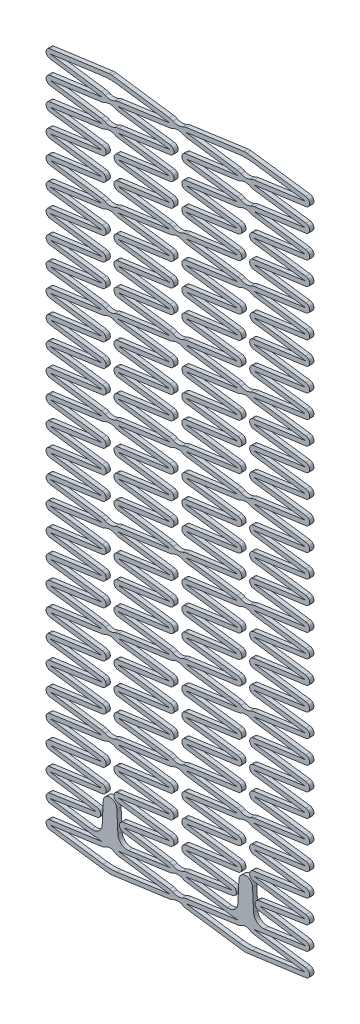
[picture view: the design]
SolidWorks part; units mm, degrees
ref_plane "Ebene vorne" through (0, 0, 0) normal (0, 0, 1) x (1, 0, 0)
ref_plane "Ebene oben" through (0, 0, 0) normal (0, 1, 0) x (1, 0, 0)
ref_plane "Ebene rechts" through (0, 0, 0) normal (1, 0, 0) x (0, 0, -1)
sketch "Skizze1" plane through (0, 0, 0) normal (0, 0, 1) x (1, 0, 0)
  line L0 (43.7003, 7.0015) -> (41.2898, 6.6632)
  line L1 (38.0663, 7.0015) -> (40.4767, 6.6632)
  line L2 (41.2898, 6.2523) -> (43.7003, 5.914)
  line L3 (40.4767, 6.2523) -> (38.0663, 5.914)
  line L4 (47.6978, 14.952) -> (50.1083, 14.6137)
  line L5 (46.8847, 14.952) -> (44.4743, 14.6137)
  line L6 (50.1083, 15.7012) -> (47.6978, 15.3629)
  line L7 (44.4743, 15.7012) -> (46.8847, 15.3629)
  line L8 (44.4743, 12.4388) -> (46.9247, 12.7771)
  line L9 (47.6578, 12.7771) -> (50.1083, 12.4388)
  line L10 (50.1083, 13.5263) -> (47.6578, 13.188)
  line L11 (44.4743, 13.5263) -> (46.9247, 13.188)
  line L12 (47.6978, 10.6022) -> (50.1083, 10.2639)
  line L13 (46.8847, 10.6022) -> (44.4743, 10.2639)
  line L14 (50.1083, 11.3513) -> (47.6978, 11.013)
  line L15 (44.4743, 11.3513) -> (46.8847, 11.013)
  line L16 (46.9247, 8.4272) -> (44.4743, 8.0889)
  line L17 (47.6578, 8.4272) -> (50.1083, 8.0889)
  line L18 (44.4743, 9.1764) -> (46.9247, 8.8381)
  line L19 (50.1083, 9.1764) -> (47.6578, 8.8381)
  line L20 (47.6978, 6.2523) -> (50.1083, 5.914)
  line L21 (46.8847, 6.2523) -> (44.4743, 5.914)
  line L22 (50.1083, 7.0015) -> (47.6978, 6.6632)
  line L23 (44.4743, 7.0015) -> (46.8847, 6.6632)
  line L24 (46.9247, 4.0773) -> (44.4743, 3.739)
  line L25 (47.6578, 4.0773) -> (50.1083, 3.739)
  line L26 (44.4743, 4.8265) -> (46.9247, 4.4882)
  line L27 (50.1083, 4.8265) -> (47.6578, 4.4882)
  line L28 (47.6978, 1.9024) -> (50.1083, 1.5641)
  line L29 (46.8847, 1.9024) -> (44.4743, 1.5641)
  line L30 (50.1083, 2.6516) -> (47.6978, 2.3133)
  line L31 (44.4743, 2.6516) -> (46.8847, 2.3133)
  line L32 (41.2703, 19.5074) -> (43.7207, 19.1691)
  line L33 (44.4538, 19.1691) -> (46.9043, 19.5074)
  line L34 (43.7207, 18.7582) -> (41.2703, 18.4199)
  line L35 (44.4538, 18.7582) -> (46.9043, 18.4199)
  line L36 (41.2703, 15.1575) -> (43.7207, 14.8192)
  line L37 (44.4538, 14.8192) -> (46.9043, 15.1575)
  line L38 (43.7207, 14.4083) -> (41.2703, 14.07)
  line L39 (44.4538, 14.4083) -> (46.9043, 14.07)
  line L40 (44.4538, 10.0584) -> (46.9043, 9.7201)
  line L41 (46.9043, 10.8076) -> (44.4538, 10.4693)
  line L42 (41.2703, 10.8076) -> (43.7207, 10.4693)
  line L43 (43.7207, 10.0584) -> (41.2703, 9.7201)
  line L44 (44.4538, 7.8835) -> (46.9043, 7.5452)
  line L45 (43.7207, 7.8835) -> (41.2703, 7.5452)
  line L46 (46.9043, 8.6327) -> (44.4538, 8.2944)
  line L47 (41.2703, 8.6327) -> (43.7207, 8.2944)
  line L48 (44.4538, 3.5336) -> (46.9043, 3.1953)
  line L49 (43.7207, 3.5336) -> (41.2703, 3.1953)
  line L50 (46.9043, 4.2828) -> (44.4538, 3.9445)
  line L51 (41.2703, 4.2828) -> (43.7207, 3.9445)
  line L52 (41.2498, 12.7771) -> (43.7003, 12.4388)
  line L53 (40.5167, 12.7771) -> (38.0663, 12.4388)
  line L54 (43.7003, 13.5263) -> (41.2498, 13.188)
  line L55 (38.0663, 13.5263) -> (40.5167, 13.188)
  line L56 (41.2498, 8.4272) -> (43.7003, 8.0889)
  line L57 (40.5167, 8.4272) -> (38.0663, 8.0889)
  line L58 (43.7003, 9.1764) -> (41.2498, 8.8381)
  line L59 (38.0663, 9.1764) -> (40.5167, 8.8381)
  line L60 (43.7003, 4.8265) -> (41.2498, 4.4882)
  line L61 (38.0663, 4.8265) -> (40.5167, 4.4882)
  line L62 (40.5167, 4.0773) -> (38.0663, 3.739)
  line L63 (41.2498, 4.0773) -> (43.7003, 3.739)
  line L64 (41.2703, 1.0204) -> (43.7207, 0.6821)
  line L65 (43.7207, 0.2712) -> (41.2703, -0.0671)
  line L66 (43.7003, 0.4766) -> (41.2498, 0.1383)
  line L67 (44.4538, 0.2712) -> (46.9043, -0.0671)
  line L68 (44.4743, 0.4766) -> (46.9247, 0.1383)
  line L69 (46.9043, 1.0204) -> (44.4538, 0.6821)
  line L70 (44.4743, -0.6108) -> (46.9247, -0.9491)
  line L71 (41.2703, -0.0671) -> (43.7207, -0.4054)
  line L72 (41.2498, -0.2725) -> (43.7003, -0.6108)
  line L73 (43.7207, -0.8163) -> (41.2703, -1.1546)
  line L74 (43.7003, -0.6108) -> (41.2498, -0.9491)
  line L75 (44.4538, -0.8163) -> (46.9043, -1.1546)
  line L76 (46.9247, -0.2725) -> (44.4743, -0.6108)
  line L77 (46.9043, -0.0671) -> (44.4538, -0.4054)
  line L78 (47.6783, 2.1078) -> (50.1287, 1.7695)
  line L79 (50.1287, 1.3587) -> (47.6783, 1.0204)
  line L80 (50.1083, 0.4766) -> (47.6578, 0.1383)
  line L81 (50.1287, 0.2712) -> (47.6783, -0.0671)
  line L82 (47.6783, 1.0204) -> (50.1287, 0.6821)
  line L83 (47.6578, -0.2725) -> (50.1083, -0.6108)
  line L84 (47.6783, -0.0671) -> (50.1287, -0.4054)
  line L85 (50.1083, -0.6108) -> (47.6578, -0.9491)
  line L86 (50.1287, -0.8163) -> (47.6783, -1.1546)
  line L87 (40.4963, 2.1078) -> (38.0458, 1.7695)
  line L88 (38.0458, 1.3587) -> (40.4963, 1.0204)
  line L89 (38.0663, 0.4766) -> (40.5167, 0.1383)
  line L90 (38.0458, 0.2712) -> (40.4963, -0.0671)
  line L91 (40.4963, 1.0204) -> (38.0458, 0.6821)
  line L92 (38.0663, -0.6108) -> (40.5167, -0.9491)
  line L93 (38.0458, -0.8163) -> (40.4963, -1.1546)
  line L94 (40.4963, -0.0671) -> (38.0458, -0.4054)
  line L95 (40.5167, -0.2725) -> (38.0663, -0.6108)
  line L96 (47.6783, 6.4577) -> (50.1287, 6.1194)
  line L97 (50.1287, 5.7086) -> (47.6783, 5.3702)
  line L98 (38.0458, 5.7086) -> (40.4963, 5.3702)
  line L99 (40.4963, 6.4577) -> (38.0458, 6.1194)
  line L100 (47.6783, 8.6327) -> (50.1287, 8.2944)
  line L101 (50.1287, 7.8835) -> (47.6783, 7.5452)
  line L102 (50.1287, 6.796) -> (47.6783, 6.4577)
  line L103 (47.6783, 7.5452) -> (50.1287, 7.2069)
  line L104 (44.4938, -6.2536) -> (46.9043, -6.5919)
  line L105 (41.2703, -6.5919) -> (43.6807, -6.2536)
  line L106 (41.529, -5.5045) -> (43.6807, -5.8428)
  line L107 (46.6456, -5.5045) -> (44.4938, -5.8428)
  line L108 (44.4938, -7.3411) -> (47.2006, -7.721)
  line L109 (40.974, -7.721) -> (43.6807, -7.3411)
  line L110 (41.2703, -6.5919) -> (43.6807, -6.9302)
  line L111 (46.9043, -6.5919) -> (44.4938, -6.9302)
  line L112 (40.2376, -5.5045) -> (38.0458, -5.8428)
  line L113 (40.258, -5.7099) -> (38.0663, -6.0482)
  line L114 (38.0458, -5.1661) -> (40.2376, -5.5045)
  line L115 (38.0663, -4.9607) -> (40.258, -5.299)
  line L116 (40.4963, 14.07) -> (38.0458, 13.7317)
  line L117 (40.4963, -4.417) -> (38.0458, -4.7553)
  line L118 (40.5167, -4.6224) -> (38.0663, -4.9607)
  line L119 (38.0458, 13.3208) -> (40.4963, 12.9825)
  line L120 (41.5085, -5.7099) -> (43.7003, -6.0482)
  line L121 (46.666, -5.7099) -> (44.4743, -6.0482)
  line L122 (50.1287, 13.3208) -> (47.6783, 12.9825)
  line L123 (47.6783, -4.417) -> (50.1287, -4.7553)
  line L124 (47.6578, -4.6224) -> (50.1083, -4.9607)
  line L125 (47.6783, 14.07) -> (50.1287, 13.7317)
  line L126 (47.9165, -5.299) -> (50.1083, -4.9607)
  line L127 (47.937, -5.5045) -> (50.1287, -5.1661)
  line L128 (47.937, -5.5045) -> (50.1287, -5.8428)
  line L129 (47.9165, -5.7099) -> (50.1083, -6.0482)
  line L130 (38.0663, -7.1357) -> (40.4767, -6.7974)
  line L131 (41.2898, -6.7974) -> (43.7003, -7.1357)
  line L132 (41.758, -6.3285) -> (43.7003, -6.0482)
  line L133 (47.6783, -6.5919) -> (50.1287, -6.2536)
  line L134 (50.1083, -7.1357) -> (47.6978, -6.7974)
  line L135 (50.1287, -6.9302) -> (47.6783, -6.5919)
  line L136 (47.3375, -7.7213) -> (50.1287, -7.3411)
  line L137 (47.6231, -7.4832) -> (50.1083, -7.1357)
  line L138 (44.4743, -7.1357) -> (46.8847, -6.7974)
  line L139 (46.9594, -7.4832) -> (44.4743, -7.1357)
  line L140 (41.2151, -7.4832) -> (43.7003, -7.1357)
  line L141 (40.0086, -6.3285) -> (38.0663, -6.0482)
  line L142 (40.4963, -6.5919) -> (38.0458, -6.2536)
  line L143 (38.0458, -6.9302) -> (40.4963, -6.5919)
  line L144 (40.5514, -7.4832) -> (38.0663, -7.1357)
  line L145 (40.837, -7.7213) -> (38.0458, -7.3411)
  line L146 (40.562, -4.9079) -> (40.5126, -5.9161)
  line L147 (41.2046, -4.9079) -> (41.254, -5.9161)
  line L148 (46.97, -4.9079) -> (46.9206, -5.9161)
  line L149 (47.6126, -4.9079) -> (47.662, -5.9161)
  line L150 (46.4166, -6.3285) -> (44.4743, -6.0482)
  line L151 (48.166, -6.3285) -> (50.1083, -6.0482)
  line L152 (38.0663, 24.401) -> (40.4767, 24.0627)
  line L153 (47.6578, 17.127) -> (50.1083, 16.7887)
  line L154 (47.6783, 17.3324) -> (50.1287, 16.9941)
  line L155 (47.6783, 17.3324) -> (50.1287, 17.6707)
  line L156 (47.6578, 17.5379) -> (50.1278, 17.8762)
  line L157 (47.6578, 21.4769) -> (50.1083, 21.1386)
  line L158 (47.6783, 21.6823) -> (50.1287, 21.344)
  line L159 (47.6783, 21.6823) -> (50.1287, 22.0206)
  line L160 (47.6578, 21.8877) -> (50.1083, 22.226)
  line L161 (44.4743, 20.0511) -> (46.9043, 19.7128)
  line L162 (44.4743, 22.226) -> (46.8847, 22.5643)
  line L163 (44.4538, 22.4315) -> (46.9043, 22.7698)
  line L164 (41.2498, 16.0395) -> (43.7003, 15.7012)
  line L165 (41.2498, 16.4504) -> (43.7003, 16.7887)
  line L166 (41.2498, 20.8003) -> (43.7003, 21.1386)
  line L167 (41.2498, 20.3894) -> (43.7003, 20.0511)
  line L168 (41.2898, 24.0627) -> (43.7003, 24.401)
  line L169 (41.2703, 23.8572) -> (43.6807, 24.1955)
  line L170 (41.2703, 23.8572) -> (43.7207, 23.5189)
  line L171 (41.2898, 23.6518) -> (43.7003, 23.3135)
  line L172 (47.6783, 23.8572) -> (50.1287, 23.5189)
  line L173 (47.6978, 23.6518) -> (50.1083, 23.3135)
  line L174 (50.1083, 23.3135) -> (47.6978, 22.9752)
  line L175 (50.1287, 23.1081) -> (47.6783, 22.7698)
  line L176 (47.6783, 22.7698) -> (50.1287, 22.4315)
  line L177 (47.6978, 22.5643) -> (50.1083, 22.226)
  line L178 (50.1083, 24.401) -> (47.6978, 24.0627)
  line L179 (50.1287, 24.1955) -> (47.6783, 23.8572)
  line L180 (47.3375, 24.9866) -> (50.1287, 24.6064)
  line L181 (47.6231, 24.7485) -> (50.1083, 24.401)
  line L182 (50.1287, 20.9331) -> (47.6783, 20.5948)
  line L183 (50.1083, 21.1386) -> (47.6578, 20.8003)
  line L184 (47.6783, 20.5948) -> (50.1287, 20.2565)
  line L185 (47.6578, 20.3894) -> (50.1278, 20.0511)
  line L186 (47.6783, 19.5074) -> (50.1287, 19.1691)
  line L187 (50.1083, 16.7887) -> (47.6578, 16.4504)
  line L188 (50.1287, 16.5833) -> (47.6783, 16.2449)
  line L189 (47.7174, 19.3019) -> (50.1278, 18.9636)
  line L190 (47.6783, 18.4199) -> (50.1287, 18.0816)
  line L191 (50.1287, 18.7582) -> (47.6783, 18.4199)
  line L192 (50.1278, 20.0511) -> (47.7174, 19.7128)
  line L193 (50.1287, 19.8457) -> (47.6783, 19.5074)
  line L194 (47.6783, 16.2449) -> (50.1287, 15.9066)
  line L195 (47.6578, 16.0395) -> (50.1083, 15.7012)
  line L196 (47.6783, 15.1575) -> (50.1287, 14.8192)
  line L197 (50.1287, 14.4083) -> (47.6783, 14.07)
  line L198 (50.1287, 15.4958) -> (47.6783, 15.1575)
  line L199 (44.4743, 24.401) -> (46.8847, 24.0627)
  line L200 (44.4938, 24.1955) -> (46.9043, 23.8572)
  line L201 (46.9043, 23.8572) -> (44.4538, 23.5189)
  line L202 (46.8847, 23.6518) -> (44.4743, 23.3135)
  line L203 (44.4743, 23.3135) -> (46.8847, 22.9752)
  line L204 (44.4538, 23.1081) -> (46.9043, 22.7698)
  line L205 (47.2006, 24.9863) -> (44.4938, 24.6064)
  line L206 (46.9594, 24.7485) -> (44.4743, 24.401)
  line L207 (44.4538, 22.0206) -> (46.9043, 21.6823)
  line L208 (44.4743, 22.226) -> (46.9247, 21.8877)
  line L209 (46.9247, 21.4769) -> (44.4743, 21.1386)
  line L210 (44.4743, 21.1386) -> (46.9247, 20.8003)
  line L211 (46.9043, 18.4199) -> (44.4538, 18.0816)
  line L212 (46.9043, 19.3019) -> (44.4938, 18.9636)
  line L213 (46.9247, 17.127) -> (44.4743, 16.7887)
  line L214 (44.4938, 17.8762) -> (46.9247, 17.5379)
  line L215 (44.4538, 17.6707) -> (46.9043, 17.3324)
  line L216 (46.9247, 20.3894) -> (44.4743, 20.0511)
  line L217 (44.4743, 16.7887) -> (46.9247, 16.4504)
  line L218 (46.9247, 16.0395) -> (44.4743, 15.7012)
  line L219 (40.974, 24.9863) -> (43.6807, 24.6064)
  line L220 (41.2151, 24.7485) -> (43.7003, 24.401)
  line L221 (43.7003, 23.3135) -> (41.2898, 22.9752)
  line L222 (43.7207, 23.1081) -> (41.2703, 22.7698)
  line L223 (41.2703, 22.7698) -> (43.7207, 22.4315)
  line L224 (41.2898, 22.5643) -> (43.7003, 22.226)
  line L225 (43.7207, 22.0206) -> (41.2703, 21.6823)
  line L226 (43.7003, 22.226) -> (41.2498, 21.8877)
  line L227 (41.2498, 21.4769) -> (43.7003, 21.1386)
  line L228 (43.7003, 17.8762) -> (41.2498, 17.5379)
  line L229 (43.7207, 17.6707) -> (41.2703, 17.3324)
  line L230 (41.2703, 18.4199) -> (43.7207, 18.0816)
  line L231 (41.2498, 17.127) -> (43.7003, 16.7887)
  line L232 (40.4963, 17.3324) -> (38.0458, 16.9941)
  line L233 (40.5167, 17.127) -> (38.0663, 16.7887)
  line L234 (40.4963, 16.2449) -> (38.0458, 15.9066)
  line L235 (40.5167, 16.0395) -> (38.0663, 15.7012)
  line L236 (38.0458, 15.4958) -> (40.4963, 15.1575)
  line L237 (38.0458, 14.4083) -> (40.4963, 14.07)
  line L238 (40.4963, 15.1575) -> (38.0458, 14.8192)
  line L239 (38.0663, 16.7887) -> (40.5167, 16.4504)
  line L240 (38.0458, 16.5833) -> (40.4963, 16.2449)
  line L241 (38.0458, 17.6707) -> (40.4963, 17.3324)
  line L242 (38.0663, 17.8762) -> (40.5167, 17.5379)
  line L243 (40.4963, 21.6823) -> (38.0458, 21.344)
  line L244 (40.5167, 21.4769) -> (38.0663, 21.1386)
  line L245 (40.4963, 20.5948) -> (38.0458, 20.2565)
  line L246 (40.5167, 20.3894) -> (38.0663, 20.0511)
  line L247 (38.0458, 19.8457) -> (40.4963, 19.5074)
  line L248 (38.0458, 18.7582) -> (40.4963, 18.4199)
  line L249 (40.4963, 18.4199) -> (38.0458, 18.0816)
  line L250 (40.4963, 19.5074) -> (38.0458, 19.1691)
  line L251 (38.0663, 21.1386) -> (40.5167, 20.8003)
  line L252 (38.0458, 20.9331) -> (40.4963, 20.5948)
  line L253 (38.0458, 22.0206) -> (40.4963, 21.6823)
  line L254 (38.0663, 22.226) -> (40.5167, 21.8877)
  line L255 (40.4963, 22.7698) -> (38.0458, 22.4315)
  line L256 (40.4767, 22.5643) -> (38.0663, 22.226)
  line L257 (38.0458, 23.1081) -> (40.4963, 22.7698)
  line L258 (38.0663, 23.3135) -> (40.4767, 22.9752)
  line L259 (40.4767, 23.6518) -> (38.0663, 23.3135)
  line L260 (40.4963, 23.8572) -> (38.0458, 23.5189)
  line L261 (38.0458, 24.1955) -> (40.4963, 23.8572)
  line L262 (40.5514, 24.7485) -> (38.0663, 24.401)
  line L263 (40.837, 24.9866) -> (38.0458, 24.6064)
  line L264 (40.4963, 10.8076) -> (38.0458, 10.4693)
  line L265 (38.0458, 10.0584) -> (40.4963, 9.7201)
  line L266 (47.6783, 10.8076) -> (50.1287, 10.4693)
  line L267 (50.1287, 10.0584) -> (47.6783, 9.7201)
  line L268 (38.0458, 8.971) -> (40.4963, 8.6327)
  line L269 (40.4963, 9.7201) -> (38.0458, 9.3818)
  line L270 (50.1287, 8.971) -> (47.6783, 8.6327)
  line L271 (47.6783, 9.7201) -> (50.1287, 9.3818)
  line L272 (47.6783, 11.8951) -> (50.1287, 11.5568)
  line L273 (47.6578, 11.6896) -> (50.1083, 11.3513)
  line L274 (50.1287, 11.1459) -> (47.6783, 10.8076)
  line L275 (50.1083, 12.4388) -> (47.6578, 12.1005)
  line L276 (50.1287, 12.2334) -> (47.6783, 11.8951)
  line L277 (47.6783, 12.9825) -> (50.1287, 12.6442)
  line L278 (40.5167, 11.6896) -> (38.0663, 11.3513)
  line L279 (40.4963, 11.8951) -> (38.0458, 11.5568)
  line L280 (38.0458, 11.1459) -> (40.4963, 10.8076)
  line L281 (38.0663, 12.4388) -> (40.5167, 12.1005)
  line L282 (38.0458, 12.2334) -> (40.4963, 11.8951)
  line L283 (40.4963, 12.9825) -> (38.0458, 12.6442)
  line L284 (41.2703, 9.7201) -> (43.7207, 9.3818)
  line L285 (43.7207, 8.971) -> (41.2703, 8.6327)
  line L286 (44.4538, 8.971) -> (46.9043, 8.6327)
  line L287 (46.9043, 9.7201) -> (44.4538, 9.3818)
  line L288 (46.9247, 11.6896) -> (44.4743, 11.3513)
  line L289 (41.2498, 11.6896) -> (43.7003, 11.3513)
  line L290 (41.2703, 12.9825) -> (43.7207, 12.6442)
  line L291 (43.7207, 12.2334) -> (41.2703, 11.8951)
  line L292 (43.7003, 12.4388) -> (41.2498, 12.1005)
  line L293 (44.4538, 12.2334) -> (46.9043, 11.8951)
  line L294 (44.4743, 12.4388) -> (46.9247, 12.1005)
  line L295 (46.9043, 12.9825) -> (44.4538, 12.6442)
  line L296 (41.2498, -4.6224) -> (43.7003, -4.9607)
  line L297 (41.2703, -4.417) -> (43.7207, -4.7553)
  line L298 (46.9043, -4.417) -> (44.4538, -4.7553)
  line L299 (46.9247, -4.6224) -> (44.4743, -4.9607)
  line L300 (41.5085, -5.299) -> (43.7003, -4.9607)
  line L301 (41.529, -5.5045) -> (43.7207, -5.1661)
  line L302 (44.4743, -4.9607) -> (46.666, -5.299)
  line L303 (44.4538, -5.1661) -> (46.6456, -5.5045)
  line L304 (46.9043, 14.07) -> (44.4538, 13.7317)
  line L305 (44.4538, 13.3208) -> (46.9043, 12.9825)
  line L306 (43.7207, 13.3208) -> (41.2703, 12.9825)
  line L307 (41.2703, 14.07) -> (43.7207, 13.7317)
  line L308 (44.4538, 16.9941) -> (46.9043, 17.3324)
  line L309 (44.4538, 16.5833) -> (46.9043, 16.2449)
  line L310 (43.7207, 16.5833) -> (41.2703, 16.2449)
  line L311 (41.2703, 17.3324) -> (43.7207, 16.9941)
  line L312 (44.4538, 20.9331) -> (46.9043, 20.5948)
  line L313 (44.4538, 21.344) -> (46.9043, 21.6823)
  line L314 (43.7207, 20.9331) -> (41.2703, 20.5948)
  line L315 (41.2703, 21.6823) -> (43.7207, 21.344)
  line L316 (40.4963, 7.5452) -> (38.0458, 7.2069)
  line L317 (38.0458, 6.796) -> (40.4963, 6.4577)
  line L318 (38.0458, 7.8835) -> (40.4963, 7.5452)
  line L319 (40.4963, 8.6327) -> (38.0458, 8.2944)
  line L320 (40.4963, 4.2828) -> (38.0458, 3.9445)
  line L321 (38.0458, 3.5336) -> (40.4963, 3.1953)
  line L322 (38.0663, 3.739) -> (40.5167, 3.4007)
  line L323 (38.0458, 4.6211) -> (40.4963, 4.2828)
  line L324 (40.4963, 5.3702) -> (38.0458, 5.0319)
  line L325 (47.6783, 4.2828) -> (50.1287, 3.9445)
  line L326 (50.1287, 3.5336) -> (47.6783, 3.1953)
  line L327 (50.1083, 3.739) -> (47.6578, 3.4007)
  line L328 (50.1287, 4.6211) -> (47.6783, 4.2828)
  line L329 (47.6783, 5.3702) -> (50.1287, 5.0319)
  line L330 (44.4743, 3.739) -> (46.9247, 3.4007)
  line L331 (43.7003, 3.739) -> (41.2498, 3.4007)
  line L332 (41.2703, 5.3702) -> (43.7207, 5.0319)
  line L333 (43.7207, 4.6211) -> (41.2703, 4.2828)
  line L334 (44.4538, 4.6211) -> (46.9043, 4.2828)
  line L335 (46.9043, 5.3702) -> (44.4538, 5.0319)
  line L336 (38.0458, 2.4461) -> (40.4963, 2.1078)
  line L337 (40.4963, 3.1953) -> (38.0458, 2.857)
  line L338 (40.5167, 2.9899) -> (38.0663, 2.6516)
  line L339 (50.1287, 2.4461) -> (47.6783, 2.1078)
  line L340 (47.6578, 2.9899) -> (50.1083, 2.6516)
  line L341 (47.6783, 3.1953) -> (50.1287, 2.857)
  line L342 (41.2498, 2.9899) -> (43.7003, 2.6516)
  line L343 (46.9247, 2.9899) -> (44.4743, 2.6516)
  line L344 (43.7003, 8.0889) -> (41.2498, 7.7506)
  line L345 (38.0663, 8.0889) -> (40.5167, 7.7506)
  line L346 (40.5167, 7.3398) -> (38.0663, 7.0015)
  line L347 (41.2498, 7.3398) -> (43.7003, 7.0015)
  line L348 (50.1083, 8.0889) -> (47.6578, 7.7506)
  line L349 (44.4743, 8.0889) -> (46.9247, 7.7506)
  line L350 (47.6578, 7.3398) -> (50.1083, 7.0015)
  line L351 (46.9247, 7.3398) -> (44.4743, 7.0015)
  line L352 (40.5167, -3.5349) -> (38.0663, -3.8732)
  line L353 (40.4963, -3.3295) -> (38.0458, -3.6678)
  line L354 (38.0458, -4.0787) -> (40.4963, -4.417)
  line L355 (38.0663, -3.8732) -> (40.5167, -4.2115)
  line L356 (40.4963, -2.242) -> (38.0458, -2.5803)
  line L357 (38.0458, -2.9912) -> (40.4963, -3.3295)
  line L358 (38.0663, -2.7858) -> (40.5167, -3.1241)
  line L359 (38.0458, -1.9037) -> (40.4963, -2.242)
  line L360 (40.4963, -1.1546) -> (38.0458, -1.4929)
  line L361 (40.5167, -1.36) -> (38.0663, -1.6983)
  line L362 (50.1287, -4.0787) -> (47.6783, -4.417)
  line L363 (50.1083, -3.8732) -> (47.6578, -4.2115)
  line L364 (47.6783, -3.3295) -> (50.1287, -3.6678)
  line L365 (47.6578, -3.5349) -> (50.1083, -3.8732)
  line L366 (47.6783, -2.242) -> (50.1287, -2.5803)
  line L367 (50.1287, -2.9912) -> (47.6783, -3.3295)
  line L368 (50.1083, -2.7858) -> (47.6578, -3.1241)
  line L369 (50.1287, -1.9037) -> (47.6783, -2.242)
  line L370 (47.6578, -1.36) -> (50.1083, -1.6983)
  line L371 (47.6783, -1.1546) -> (50.1287, -1.4929)
  line L372 (46.9043, -3.3295) -> (44.4538, -3.6678)
  line L373 (46.9247, -3.5349) -> (44.4743, -3.8732)
  line L374 (44.4538, -4.0787) -> (46.9043, -4.417)
  line L375 (43.7003, -3.8732) -> (41.2498, -4.2115)
  line L376 (43.7207, -4.0787) -> (41.2703, -4.417)
  line L377 (41.2498, -3.5349) -> (43.7003, -3.8732)
  line L378 (41.2703, -3.3295) -> (43.7207, -3.6678)
  line L379 (44.4743, -3.8732) -> (46.9247, -4.2115)
  line L380 (46.9043, -2.242) -> (44.4538, -2.5803)
  line L381 (44.4743, -2.7858) -> (46.9247, -3.1241)
  line L382 (44.4538, -2.9912) -> (46.9043, -3.3295)
  line L383 (43.7003, -2.7858) -> (41.2498, -3.1241)
  line L384 (43.7207, -2.9912) -> (41.2703, -3.3295)
  line L385 (41.2703, -2.242) -> (43.7207, -2.5803)
  line L386 (41.2498, -1.36) -> (43.7003, -1.6983)
  line L387 (46.9247, -1.36) -> (44.4743, -1.6983)
  line L388 (40.4767, -2.4475) -> (38.0663, -2.7858)
  line L389 (41.2898, -2.4475) -> (43.7003, -2.7858)
  line L390 (38.0663, -1.6983) -> (40.4767, -2.0366)
  line L391 (43.7003, -1.6983) -> (41.2898, -2.0366)
  line L392 (41.2498, 0.8149) -> (43.7003, 0.4766)
  line L393 (40.5167, 0.8149) -> (38.0663, 0.4766)
  line L394 (38.0663, 1.5641) -> (40.5167, 1.2258)
  line L395 (43.7003, 1.5641) -> (41.2498, 1.2258)
  line L396 (40.4767, 1.9024) -> (38.0663, 1.5641)
  line L397 (41.2898, 1.9024) -> (43.7003, 1.5641)
  line L398 (38.0663, 2.6516) -> (40.4767, 2.3133)
  line L399 (43.7003, 2.6516) -> (41.2898, 2.3133)
  line L400 (41.2498, 5.1648) -> (43.7003, 4.8265)
  line L401 (40.5167, 5.1648) -> (38.0663, 4.8265)
  line L402 (38.0663, 5.914) -> (40.5167, 5.5757)
  line L403 (43.7003, 5.914) -> (41.2498, 5.5757)
  line L404 (38.0663, 10.2639) -> (40.5167, 9.9256)
  line L405 (43.7003, 10.2639) -> (41.2498, 9.9256)
  line L406 (40.5167, 9.5147) -> (38.0663, 9.1764)
  line L407 (41.2498, 9.5147) -> (43.7003, 9.1764)
  line L408 (41.2898, 10.6022) -> (43.7003, 10.2639)
  line L409 (40.4767, 10.6022) -> (38.0663, 10.2639)
  line L410 (43.7003, 11.3513) -> (41.2898, 11.013)
  line L411 (38.0663, 11.3513) -> (40.4767, 11.013)
  line L412 (38.0663, 14.6137) -> (40.5167, 14.2754)
  line L413 (43.7003, 14.6137) -> (41.2498, 14.2754)
  line L414 (40.5167, 13.8646) -> (38.0663, 13.5263)
  line L415 (41.2498, 13.8646) -> (43.7003, 13.5263)
  line L416 (43.7003, 15.7012) -> (41.2898, 15.3629)
  line L417 (38.0663, 15.7012) -> (40.4767, 15.3629)
  line L418 (40.4767, 14.952) -> (38.0663, 14.6137)
  line L419 (41.2898, 14.952) -> (43.7003, 14.6137)
  line L420 (40.5167, 18.2145) -> (38.0663, 17.8762)
  line L421 (41.2498, 18.2145) -> (43.7003, 17.8762)
  line L422 (38.0663, 18.9636) -> (40.5167, 18.6253)
  line L423 (43.7003, 18.9636) -> (41.2498, 18.6253)
  line L424 (43.7003, 20.0511) -> (41.2898, 19.7128)
  line L425 (38.0663, 20.0511) -> (40.4767, 19.7128)
  line L426 (41.2898, 19.3019) -> (43.7003, 18.9636)
  line L427 (38.0663, 18.9636) -> (40.4767, 19.3019)
  line L428 (46.9043, -1.1546) -> (44.4938, -1.4929)
  line L429 (41.2703, -1.1546) -> (43.6807, -1.4929)
  line L430 (44.4938, -1.9037) -> (46.9043, -2.242)
  line L431 (43.6807, -1.9037) -> (41.2703, -2.242)
  line L432 (46.9043, 2.1078) -> (44.4538, 1.7695)
  line L433 (41.2703, 2.1078) -> (43.7207, 1.7695)
  line L434 (44.4538, 1.3587) -> (46.9043, 1.0204)
  line L435 (43.7207, 1.3587) -> (41.2703, 1.0204)
  line L436 (44.4938, 2.4461) -> (46.9043, 2.1078)
  line L437 (43.6807, 2.4461) -> (41.2703, 2.1078)
  line L438 (46.9043, 3.1953) -> (44.4938, 2.857)
  line L439 (41.2703, 3.1953) -> (43.6807, 2.857)
  line L440 (46.9043, 6.4577) -> (44.4538, 6.1194)
  line L441 (41.2703, 6.4577) -> (43.7207, 6.1194)
  line L442 (44.4538, 5.7086) -> (46.9043, 5.3702)
  line L443 (43.7207, 5.7086) -> (41.2703, 5.3702)
  line L444 (41.2703, 7.5452) -> (43.6807, 7.2069)
  line L445 (46.9043, 7.5452) -> (44.4938, 7.2069)
  line L446 (43.6807, 6.796) -> (41.2703, 6.4577)
  line L447 (44.4938, 6.796) -> (46.9043, 6.4577)
  line L448 (41.2703, 11.8951) -> (43.6807, 11.5568)
  line L449 (46.9043, 11.8951) -> (44.4938, 11.5568)
  line L450 (43.6807, 11.1459) -> (41.2703, 10.8076)
  line L451 (44.4938, 11.1459) -> (46.9043, 10.8076)
  line L452 (41.2703, 16.2449) -> (43.6807, 15.9066)
  line L453 (46.9043, 16.2449) -> (44.4938, 15.9066)
  line L454 (44.4938, 15.4958) -> (46.9043, 15.1575)
  line L455 (43.6807, 15.4958) -> (41.2703, 15.1575)
  line L456 (41.2703, 20.5948) -> (43.6807, 20.2565)
  line L457 (46.9043, 20.5948) -> (44.4938, 20.2565)
  line L458 (41.2703, 19.5074) -> (43.6807, 19.8457)
  line L459 (44.4938, 19.8457) -> (46.9043, 19.5074)
  line L460 (44.4938, 18.9636) -> (46.9443, 18.6253)
  line L461 (47.6774, 18.6253) -> (50.1278, 18.9636)
  line L462 (46.9443, 18.2145) -> (44.4938, 17.8762)
  line L463 (47.6774, 18.2145) -> (50.1278, 17.8762)
  line L464 (44.4743, 14.6137) -> (46.9247, 14.2754)
  line L465 (50.1083, 14.6137) -> (47.6578, 14.2754)
  line L466 (47.6578, 13.8646) -> (50.1083, 13.5263)
  line L467 (44.4743, 13.5263) -> (46.9247, 13.8646)
  line L468 (50.1083, 10.2639) -> (47.6578, 9.9256)
  line L469 (44.4743, 10.2639) -> (46.9247, 9.9256)
  line L470 (47.6578, 9.5147) -> (50.1083, 9.1764)
  line L471 (46.9247, 9.5147) -> (44.4743, 9.1764)
  line L472 (50.1083, 5.914) -> (47.6578, 5.5757)
  line L473 (44.4743, 5.914) -> (46.9247, 5.5757)
  line L474 (47.6578, 5.1648) -> (50.1083, 4.8265)
  line L475 (46.9247, 5.1648) -> (44.4743, 4.8265)
  line L476 (50.1083, 1.5641) -> (47.6578, 1.2258)
  line L477 (44.4743, 1.5641) -> (46.9247, 1.2258)
  line L478 (47.6578, 0.8149) -> (50.1083, 0.4766)
  line L479 (46.9247, 0.8149) -> (44.4743, 0.4766)
  line L480 (44.4743, -1.6983) -> (46.8847, -2.0366)
  line L481 (50.1083, -1.6983) -> (47.6978, -2.0366)
  line L482 (47.6978, -2.4475) -> (50.1083, -2.7858)
  line L483 (46.8847, -2.4475) -> (44.4743, -2.7858)
  arc A0 (41.2898, 6.6632) -> (41.1151, 6.6088) centre (41.3485, 6.1665) ccw
  arc A1 (40.6515, 6.6088) -> (40.4767, 6.6632) centre (40.418, 6.1665) ccw
  arc A2 (40.6515, 6.6088) -> (41.1151, 6.6088) centre (40.8833, 7.0636) ccw
  arc A3 (41.1151, 6.3067) -> (40.6515, 6.3067) centre (40.8833, 5.8499) ccw
  arc A4 (41.1151, 6.3067) -> (41.2898, 6.2523) centre (41.3485, 6.7489) ccw
  arc A5 (40.4767, 6.2523) -> (40.6515, 6.3067) centre (40.418, 6.7489) ccw
  arc A6 (47.5231, 15.0064) -> (47.6978, 14.952) centre (47.7565, 15.4487) ccw
  arc A7 (46.8847, 14.952) -> (47.0595, 15.0064) centre (46.826, 15.4487) ccw
  arc A8 (47.5231, 15.0064) -> (47.0595, 15.0064) centre (47.2913, 14.5497) ccw
  arc A9 (47.6978, 15.3629) -> (47.5231, 15.3085) centre (47.7565, 14.8663) ccw
  arc A10 (47.0595, 15.3085) -> (46.8847, 15.3629) centre (46.826, 14.8663) ccw
  arc A11 (47.0595, 15.3085) -> (47.5231, 15.3085) centre (47.2913, 15.7634) ccw
  arc A12 (47.6578, 13.188) -> (47.6578, 12.7771) centre (47.6833, 12.9825) ccw
  arc A13 (46.9247, 12.7771) -> (46.9247, 13.188) centre (46.8993, 12.9825) ccw
  arc A14 (46.8847, 10.6022) -> (47.0595, 10.6566) centre (46.826, 11.0988) ccw
  arc A15 (47.5231, 10.6566) -> (47.0595, 10.6566) centre (47.2913, 10.1998) ccw
  arc A16 (47.5231, 10.6566) -> (47.6978, 10.6022) centre (47.7565, 11.0988) ccw
  arc A17 (47.0595, 10.9586) -> (47.5231, 10.9586) centre (47.2913, 11.4135) ccw
  arc A18 (47.6978, 11.013) -> (47.5231, 10.9586) centre (47.7565, 10.5164) ccw
  arc A19 (47.0595, 10.9586) -> (46.8847, 11.013) centre (46.826, 10.5164) ccw
  arc A20 (46.9247, 8.4272) -> (46.9247, 8.8381) centre (46.8993, 8.6327) ccw
  arc A21 (47.6578, 8.8381) -> (47.6578, 8.4272) centre (47.6833, 8.6327) ccw
  arc A22 (47.6978, 6.6632) -> (47.5231, 6.6088) centre (47.7565, 6.1665) ccw
  arc A23 (47.0595, 6.6088) -> (46.8847, 6.6632) centre (46.826, 6.1665) ccw
  arc A24 (47.0595, 6.6088) -> (47.5231, 6.6088) centre (47.2913, 7.0636) ccw
  arc A25 (47.5231, 6.3067) -> (47.0595, 6.3067) centre (47.2913, 5.8499) ccw
  arc A26 (47.5231, 6.3067) -> (47.6978, 6.2523) centre (47.7565, 6.7489) ccw
  arc A27 (46.8847, 6.2523) -> (47.0595, 6.3067) centre (46.826, 6.7489) ccw
  arc A28 (46.9247, 4.0773) -> (46.9247, 4.4882) centre (46.8993, 4.2828) ccw
  arc A29 (47.6578, 4.4882) -> (47.6578, 4.0773) centre (47.6833, 4.2828) ccw
  arc A30 (47.5231, 1.9568) -> (47.6978, 1.9024) centre (47.7565, 2.3991) ccw
  arc A31 (47.6978, 2.3133) -> (47.5231, 2.2589) centre (47.7565, 1.8166) ccw
  arc A32 (47.0595, 2.2589) -> (47.5231, 2.2589) centre (47.2913, 2.7138) ccw
  arc A33 (47.5231, 1.9568) -> (47.0595, 1.9568) centre (47.2913, 1.5001) ccw
  arc A34 (46.8847, 1.9024) -> (47.0595, 1.9568) centre (46.826, 2.3991) ccw
  arc A35 (47.0595, 2.2589) -> (46.8847, 2.3133) centre (46.826, 1.8166) ccw
  arc A36 (43.9023, 18.9636) -> (43.7207, 19.1691) centre (43.6953, 18.9636) ccw
  arc A37 (44.4538, 19.1691) -> (44.2723, 18.9636) centre (44.4793, 18.9636) ccw
  arc A38 (43.7207, 18.7582) -> (43.9023, 18.9636) centre (43.6953, 18.9636) ccw
  arc A39 (44.2723, 18.9636) -> (44.4538, 18.7582) centre (44.4793, 18.9636) ccw
  arc A40 (43.7207, 14.4083) -> (43.7207, 14.8192) centre (43.6953, 14.6137) ccw
  arc A41 (44.4538, 14.8192) -> (44.4538, 14.4083) centre (44.4793, 14.6137) ccw
  arc A42 (44.4538, 10.4693) -> (44.4538, 10.0584) centre (44.4793, 10.2639) ccw
  arc A43 (43.7207, 10.0584) -> (43.7207, 10.4693) centre (43.6953, 10.2639) ccw
  arc A44 (44.4538, 8.2944) -> (44.4538, 7.8835) centre (44.4793, 8.0889) ccw
  arc A45 (43.7207, 7.8835) -> (43.7207, 8.2944) centre (43.6953, 8.0889) ccw
  arc A46 (44.4538, 3.9445) -> (44.4538, 3.5336) centre (44.4793, 3.739) ccw
  arc A47 (43.7207, 3.5336) -> (43.7207, 3.9445) centre (43.6953, 3.739) ccw
  arc A48 (41.2498, 13.188) -> (41.2498, 12.7771) centre (41.2753, 12.9825) ccw
  arc A49 (40.5167, 12.7771) -> (40.5167, 13.188) centre (40.4913, 12.9825) ccw
  arc A50 (41.2498, 8.8381) -> (41.2498, 8.4272) centre (41.2753, 8.6327) ccw
  arc A51 (40.5167, 8.4272) -> (40.5167, 8.8381) centre (40.4913, 8.6327) ccw
  arc A52 (41.2498, 4.4882) -> (41.2498, 4.0773) centre (41.2753, 4.2828) ccw
  arc A53 (40.5167, 4.0773) -> (40.5167, 4.4882) centre (40.4913, 4.2828) ccw
  arc A54 (46.9247, -0.2725) -> (46.9247, 0.1383) centre (46.8993, -0.0671) ccw
  arc A55 (41.2498, 0.1383) -> (41.2498, -0.2725) centre (41.2753, -0.0671) ccw
  arc A56 (43.7207, 0.2712) -> (43.7207, 0.6821) centre (43.6953, 0.4766) ccw
  arc A57 (44.4538, 0.6821) -> (44.4538, 0.2712) centre (44.4793, 0.4766) ccw
  arc A58 (46.9247, -1.36) -> (46.9247, -0.9491) centre (46.8993, -1.1546) ccw
  arc A59 (43.7207, -0.8163) -> (43.7207, -0.4054) centre (43.6953, -0.6108) ccw
  arc A60 (44.4538, -0.4054) -> (44.4538, -0.8163) centre (44.4793, -0.6108) ccw
  arc A61 (41.2498, -0.9491) -> (41.2498, -1.36) centre (41.2753, -1.1546) ccw
  arc A62 (50.1287, 1.3587) -> (50.1287, 1.7695) centre (50.1033, 1.5641) ccw
  arc A63 (47.6578, 0.1383) -> (47.6578, -0.2725) centre (47.6833, -0.0671) ccw
  arc A64 (50.1287, 0.2712) -> (50.1287, 0.6821) centre (50.1033, 0.4766) ccw
  arc A65 (50.1287, -0.8163) -> (50.1287, -0.4054) centre (50.1033, -0.6108) ccw
  arc A66 (47.6578, -0.9491) -> (47.6578, -1.36) centre (47.6833, -1.1546) ccw
  arc A67 (38.0458, 1.7695) -> (38.0458, 1.3587) centre (38.0713, 1.5641) ccw
  arc A68 (40.5167, -0.2725) -> (40.5167, 0.1383) centre (40.4913, -0.0671) ccw
  arc A69 (38.0458, 0.6821) -> (38.0458, 0.2712) centre (38.0713, 0.4766) ccw
  arc A70 (38.0458, -0.4054) -> (38.0458, -0.8163) centre (38.0713, -0.6108) ccw
  arc A71 (40.5167, -1.36) -> (40.5167, -0.9491) centre (40.4913, -1.1546) ccw
  arc A72 (50.1287, 5.7086) -> (50.1287, 6.1194) centre (50.1033, 5.914) ccw
  arc A73 (38.0458, 6.1194) -> (38.0458, 5.7086) centre (38.0713, 5.914) ccw
  arc A74 (50.1287, 7.8835) -> (50.1287, 8.2944) centre (50.1033, 8.0889) ccw
  arc A75 (50.1287, 6.796) -> (50.1287, 7.2069) centre (50.1033, 7.0015) ccw
  arc A76 (46.8847, -6.7974) -> (47.1021, -6.7177) centre (46.826, -6.3007) ccw
  arc A77 (47.4804, -6.7177) -> (47.6978, -6.7974) centre (47.7565, -6.3007) ccw
  arc A78 (47.4804, -6.7177) -> (47.1021, -6.7177) centre (47.2913, -6.9785) ccw
  arc A79 (46.9247, 20.3894) -> (46.9247, 20.8003) centre (46.8993, 20.5948) ccw
  arc A80 (47.6578, 20.8003) -> (47.6578, 20.3894) centre (47.6833, 20.5948) ccw
  arc A81 (47.6578, 16.4504) -> (47.6578, 16.0395) centre (47.6833, 16.2449) ccw
  arc A82 (46.9247, 16.0395) -> (46.9247, 16.4504) centre (46.8993, 16.2449) ccw
  arc A83 (41.2498, 16.4504) -> (41.2498, 16.0395) centre (41.2753, 16.2449) ccw
  arc A84 (40.5167, 16.0395) -> (40.5167, 16.4504) centre (40.4913, 16.2449) ccw
  arc A85 (40.5167, 20.3894) -> (40.5167, 20.8003) centre (40.4913, 20.5948) ccw
  arc A86 (41.2498, 20.8003) -> (41.2498, 20.3894) centre (41.2753, 20.5948) ccw
  arc A87 (47.5426, 19.3563) -> (47.7174, 19.3019) centre (47.7761, 19.7986) ccw
  arc A88 (46.9043, 19.3019) -> (47.0791, 19.3563) centre (46.8456, 19.7986) ccw
  arc A89 (47.7174, 19.7128) -> (47.5426, 19.6584) centre (47.7761, 19.2161) ccw
  arc A90 (47.0791, 19.6584) -> (46.9043, 19.7128) centre (46.8456, 19.2161) ccw
  arc A91 (47.0791, 19.6584) -> (47.5426, 19.6584) centre (47.3108, 20.1133) ccw
  arc A92 (47.5426, 19.3563) -> (47.0791, 19.3563) centre (47.3108, 18.9014) ccw
  arc A93 (47.5231, 22.6187) -> (47.0595, 22.6187) centre (47.2913, 22.1639) ccw
  arc A94 (47.0595, 22.9208) -> (47.5231, 22.9208) centre (47.2913, 23.3757) ccw
  arc A95 (47.0595, 22.9208) -> (46.8847, 22.9752) centre (46.826, 22.4785) ccw
  arc A96 (47.6978, 22.9752) -> (47.5231, 22.9208) centre (47.7565, 22.4785) ccw
  arc A97 (46.8847, 22.5643) -> (47.0595, 22.6187) centre (46.826, 23.061) ccw
  arc A98 (47.5231, 22.6187) -> (47.6978, 22.5643) centre (47.7565, 23.061) ccw
  arc A99 (41.1151, 22.6187) -> (41.2898, 22.5643) centre (41.3485, 23.061) ccw
  arc A100 (40.4767, 22.5643) -> (40.6515, 22.6187) centre (40.418, 23.061) ccw
  arc A101 (41.2898, 22.9752) -> (41.1151, 22.9208) centre (41.3485, 22.4785) ccw
  arc A102 (40.6515, 22.9208) -> (40.4767, 22.9752) centre (40.418, 22.4785) ccw
  arc A103 (40.6515, 22.9208) -> (41.1151, 22.9208) centre (40.8833, 23.3757) ccw
  arc A104 (41.1151, 22.6187) -> (40.6515, 22.6187) centre (40.8833, 22.1639) ccw
  arc A105 (47.3375, 24.9866) -> (47.2006, 24.9863) centre (47.27, 24.4911) ccw
  arc A106 (40.974, 24.9863) -> (40.837, 24.9866) centre (40.9045, 24.4911) ccw
  arc A107 (47.2006, -7.721) -> (47.3375, -7.7213) centre (47.27, -7.2258) ccw
  arc A108 (40.837, -7.7213) -> (40.974, -7.721) centre (40.9045, -7.2258) ccw
  arc A109 (44.3191, -6.1992) -> (43.8555, -6.1992) centre (44.0873, -6.6541) ccw
  arc A110 (43.8555, -5.8971) -> (44.3191, -5.8971) centre (44.0873, -5.4423) ccw
  arc A111 (44.3191, -6.1992) -> (44.4938, -6.2536) centre (44.5525, -5.757) ccw
  arc A112 (43.6807, -6.2536) -> (43.8555, -6.1992) centre (43.622, -5.757) ccw
  arc A113 (44.4938, -5.8428) -> (44.3191, -5.8971) centre (44.5525, -6.3394) ccw
  arc A114 (43.8555, -5.8971) -> (43.6807, -5.8428) centre (43.622, -6.3394) ccw
  arc A115 (43.8555, -6.9846) -> (43.6807, -6.9302) centre (43.622, -7.4269) ccw
  arc A116 (44.4938, -6.9302) -> (44.3191, -6.9846) centre (44.5525, -7.4269) ccw
  arc A117 (43.6807, -7.3411) -> (43.8555, -7.2867) centre (43.622, -6.8444) ccw
  arc A118 (44.3191, -7.2867) -> (44.4938, -7.3411) centre (44.5525, -6.8444) ccw
  arc A119 (43.8555, -6.9846) -> (44.3191, -6.9846) centre (44.0873, -6.5297) ccw
  arc A120 (44.3191, -7.2867) -> (43.8555, -7.2867) centre (44.0873, -7.7416) ccw
  arc A121 (47.5231, 23.7062) -> (47.0595, 23.7062) centre (47.2913, 23.2513) ccw
  arc A122 (47.0595, 24.0083) -> (47.5231, 24.0083) centre (47.2913, 24.4632) ccw
  arc A123 (44.3191, 24.2499) -> (43.8555, 24.2499) centre (44.0873, 23.7951) ccw
  arc A124 (43.8555, 24.552) -> (44.3191, 24.552) centre (44.0873, 25.0069) ccw
  arc A125 (41.1151, 23.7062) -> (40.6515, 23.7062) centre (40.8833, 23.2513) ccw
  arc A126 (40.6515, 24.0083) -> (41.1151, 24.0083) centre (40.8833, 24.4632) ccw
  arc A127 (38.0458, 13.7317) -> (38.0458, 13.3208) centre (38.0713, 13.5263) ccw
  arc A128 (38.0458, -4.7553) -> (38.0458, -5.1661) centre (38.0713, -4.9607) ccw
  arc A129 (41.5085, -5.299) -> (41.5085, -5.7099) centre (41.534, -5.5045) ccw
  arc A130 (50.1287, 13.3208) -> (50.1287, 13.7317) centre (50.1033, 13.5263) ccw
  arc A131 (50.1287, -5.1661) -> (50.1287, -4.7553) centre (50.1033, -4.9607) ccw
  arc A132 (46.9594, -7.4832) -> (47.6231, -7.4832) centre (47.2913, -4.8037) ccw
  arc A133 (40.5514, -7.4832) -> (41.2151, -7.4832) centre (40.8833, -4.8037) ccw
  arc A134 (40.4767, -6.7974) -> (40.6941, -6.7177) centre (40.418, -6.3007) ccw
  arc A135 (41.0724, -6.7177) -> (40.6941, -6.7177) centre (40.8833, -6.9785) ccw
  arc A136 (41.0724, -6.7177) -> (41.2898, -6.7974) centre (41.3485, -6.3007) ccw
  arc A137 (50.1287, -7.3411) -> (50.1287, -6.9302) centre (50.1033, -7.1357) ccw
  arc A138 (50.1287, -6.2536) -> (50.1287, -5.8428) centre (50.1033, -6.0482) ccw
  arc A139 (38.0458, -5.8428) -> (38.0458, -6.2536) centre (38.0713, -6.0482) ccw
  arc A140 (38.0458, -6.9302) -> (38.0458, -7.3411) centre (38.0713, -7.1357) ccw
  arc A141 (41.2046, -4.9079) -> (40.562, -4.9079) centre (40.8833, -4.9079) ccw
  arc A142 (40.0086, -6.3285) -> (40.5126, -5.9161) centre (40.0639, -5.8819) ccw
  arc A143 (41.254, -5.9161) -> (41.758, -6.3285) centre (41.7027, -5.8819) ccw
  arc A144 (40.258, -5.7099) -> (40.258, -5.299) centre (40.2326, -5.5045) ccw
  arc A145 (47.9165, -5.299) -> (47.9165, -5.7099) centre (47.942, -5.5045) ccw
  arc A146 (47.6126, -4.9079) -> (46.97, -4.9079) centre (47.2913, -4.9079) ccw
  arc A147 (46.666, -5.7099) -> (46.666, -5.299) centre (46.6406, -5.5045) ccw
  arc A148 (46.4166, -6.3285) -> (46.9206, -5.9161) centre (46.4719, -5.8819) ccw
  arc A149 (47.662, -5.9161) -> (48.166, -6.3285) centre (48.1107, -5.8819) ccw
  arc A150 (46.9247, 17.127) -> (46.9247, 17.5379) centre (46.8993, 17.3324) ccw
  arc A151 (47.6578, 17.5379) -> (47.6578, 17.127) centre (47.6833, 17.3324) ccw
  arc A152 (44.2723, 22.226) -> (44.4538, 22.0206) centre (44.4793, 22.226) ccw
  arc A153 (43.7207, 22.0206) -> (43.9023, 22.226) centre (43.6953, 22.226) ccw
  arc A154 (46.9247, 21.4769) -> (46.9247, 21.8877) centre (46.8993, 21.6823) ccw
  arc A155 (47.6578, 21.8877) -> (47.6578, 21.4769) centre (47.6833, 21.6823) ccw
  arc A156 (44.4538, 22.4315) -> (44.2723, 22.226) centre (44.4793, 22.226) ccw
  arc A157 (43.9023, 22.226) -> (43.7207, 22.4315) centre (43.6953, 22.226) ccw
  arc A158 (47.0595, 24.0083) -> (46.8847, 24.0627) centre (46.826, 23.566) ccw
  arc A159 (47.6978, 24.0627) -> (47.5231, 24.0083) centre (47.7565, 23.566) ccw
  arc A160 (46.8847, 23.6518) -> (47.0595, 23.7062) centre (46.826, 24.1485) ccw
  arc A161 (47.5231, 23.7062) -> (47.6978, 23.6518) centre (47.7565, 24.1485) ccw
  arc A162 (44.3191, 24.2499) -> (44.4938, 24.1955) centre (44.5525, 24.6922) ccw
  arc A163 (43.6807, 24.1955) -> (43.8555, 24.2499) centre (43.622, 24.6922) ccw
  arc A164 (44.4938, 24.6064) -> (44.3191, 24.552) centre (44.5525, 24.1098) ccw
  arc A165 (43.8555, 24.552) -> (43.6807, 24.6064) centre (43.622, 24.1098) ccw
  arc A166 (47.6231, 24.7485) -> (46.9594, 24.7485) centre (47.2913, 22.069) ccw
  arc A167 (41.2151, 24.7485) -> (40.5514, 24.7485) centre (40.8833, 22.069) ccw
  arc A168 (40.6515, 24.0083) -> (40.4767, 24.0627) centre (40.418, 23.566) ccw
  arc A169 (41.2898, 24.0627) -> (41.1151, 24.0083) centre (41.3485, 23.566) ccw
  arc A170 (40.4767, 23.6518) -> (40.6515, 23.7062) centre (40.418, 24.1485) ccw
  arc A171 (41.1151, 23.7062) -> (41.2898, 23.6518) centre (41.3485, 24.1485) ccw
  arc A172 (50.1287, 15.4958) -> (50.1287, 15.9066) centre (50.1033, 15.7012) ccw
  arc A173 (50.1287, 19.8457) -> (50.1287, 20.2565) centre (50.1033, 20.0511) ccw
  arc A174 (50.1287, 24.1955) -> (50.1287, 24.6064) centre (50.1033, 24.401) ccw
  arc A175 (50.1287, 23.1081) -> (50.1287, 23.5189) centre (50.1033, 23.3135) ccw
  arc A176 (50.3103, 22.226) -> (50.1287, 22.4315) centre (50.1033, 22.226) ccw
  arc A177 (50.1287, 22.0206) -> (50.3103, 22.226) centre (50.1033, 22.226) ccw
  arc A178 (50.1287, 20.9331) -> (50.1287, 21.344) centre (50.1033, 21.1386) ccw
  arc A179 (50.1287, 16.5833) -> (50.1287, 16.9941) centre (50.1033, 16.7887) ccw
  arc A180 (50.1287, 17.6707) -> (50.1287, 18.0816) centre (50.1033, 17.8762) ccw
  arc A181 (50.1287, 18.7582) -> (50.1287, 19.1691) centre (50.1033, 18.9636) ccw
  arc A182 (50.1287, 14.4083) -> (50.1287, 14.8192) centre (50.1033, 14.6137) ccw
  arc A183 (44.4538, 23.5189) -> (44.4538, 23.1081) centre (44.4793, 23.3135) ccw
  arc A184 (44.4538, 18.0816) -> (44.4538, 17.6707) centre (44.4793, 17.8762) ccw
  arc A185 (43.7207, 23.1081) -> (43.7207, 23.5189) centre (43.6953, 23.3135) ccw
  arc A186 (43.7207, 17.6707) -> (43.7207, 18.0816) centre (43.6953, 17.8762) ccw
  arc A187 (41.2498, 21.8877) -> (41.2498, 21.4769) centre (41.2753, 21.6823) ccw
  arc A188 (41.2498, 17.5379) -> (41.2498, 17.127) centre (41.2753, 17.3324) ccw
  arc A189 (38.0458, 16.9941) -> (38.0458, 16.5833) centre (38.0713, 16.7887) ccw
  arc A190 (38.0458, 15.9066) -> (38.0458, 15.4958) centre (38.0713, 15.7012) ccw
  arc A191 (38.0458, 14.8192) -> (38.0458, 14.4083) centre (38.0713, 14.6137) ccw
  arc A192 (40.5167, 17.127) -> (40.5167, 17.5379) centre (40.4913, 17.3324) ccw
  arc A193 (38.0458, 21.344) -> (38.0458, 20.9331) centre (38.0713, 21.1386) ccw
  arc A194 (38.0458, 20.2565) -> (38.0458, 19.8457) centre (38.0713, 20.0511) ccw
  arc A195 (38.0458, 18.0816) -> (38.0458, 17.6707) centre (38.0713, 17.8762) ccw
  arc A196 (38.0458, 19.1691) -> (38.0458, 18.7582) centre (38.0713, 18.9636) ccw
  arc A197 (40.5167, 21.4769) -> (40.5167, 21.8877) centre (40.4913, 21.6823) ccw
  arc A198 (38.0458, 22.4315) -> (37.8643, 22.226) centre (38.0713, 22.226) ccw
  arc A199 (37.8643, 22.226) -> (38.0458, 22.0206) centre (38.0713, 22.226) ccw
  arc A200 (38.0458, 23.5189) -> (38.0458, 23.1081) centre (38.0713, 23.3135) ccw
  arc A201 (38.0458, 24.6064) -> (38.0458, 24.1955) centre (38.0713, 24.401) ccw
  arc A202 (38.0458, 10.4693) -> (38.0458, 10.0584) centre (38.0713, 10.2639) ccw
  arc A203 (50.1287, 10.0584) -> (50.1287, 10.4693) centre (50.1033, 10.2639) ccw
  arc A204 (38.0458, 9.3818) -> (38.0458, 8.971) centre (38.0713, 9.1764) ccw
  arc A205 (50.1287, 8.971) -> (50.1287, 9.3818) centre (50.1033, 9.1764) ccw
  arc A206 (50.1287, 11.1459) -> (50.1287, 11.5568) centre (50.1033, 11.3513) ccw
  arc A207 (47.6578, 12.1005) -> (47.6578, 11.6896) centre (47.6833, 11.8951) ccw
  arc A208 (50.1287, 12.2334) -> (50.1287, 12.6442) centre (50.1033, 12.4388) ccw
  arc A209 (38.0458, 11.5568) -> (38.0458, 11.1459) centre (38.0713, 11.3513) ccw
  arc A210 (40.5167, 11.6896) -> (40.5167, 12.1005) centre (40.4913, 11.8951) ccw
  arc A211 (38.0458, 12.6442) -> (38.0458, 12.2334) centre (38.0713, 12.4388) ccw
  arc A212 (43.7207, 8.971) -> (43.7207, 9.3818) centre (43.6953, 9.1764) ccw
  arc A213 (44.4538, 9.3818) -> (44.4538, 8.971) centre (44.4793, 9.1764) ccw
  arc A214 (46.9247, 11.6896) -> (46.9247, 12.1005) centre (46.8993, 11.8951) ccw
  arc A215 (41.2498, 12.1005) -> (41.2498, 11.6896) centre (41.2753, 11.8951) ccw
  arc A216 (43.7207, 12.2334) -> (43.7207, 12.6442) centre (43.6953, 12.4388) ccw
  arc A217 (44.4538, 12.6442) -> (44.4538, 12.2334) centre (44.4793, 12.4388) ccw
  arc A218 (43.7207, -5.1661) -> (43.7207, -4.7553) centre (43.6953, -4.9607) ccw
  arc A219 (44.4538, -4.7553) -> (44.4538, -5.1661) centre (44.4793, -4.9607) ccw
  arc A220 (44.4538, 13.7317) -> (44.4538, 13.3208) centre (44.4793, 13.5263) ccw
  arc A221 (43.7207, 13.3208) -> (43.7207, 13.7317) centre (43.6953, 13.5263) ccw
  arc A222 (44.4538, 16.9941) -> (44.4538, 16.5833) centre (44.4793, 16.7887) ccw
  arc A223 (43.7207, 16.5833) -> (43.7207, 16.9941) centre (43.6953, 16.7887) ccw
  arc A224 (44.2723, 21.1386) -> (44.4538, 20.9331) centre (44.4793, 21.1386) ccw
  arc A225 (44.4538, 21.344) -> (44.2723, 21.1386) centre (44.4793, 21.1386) ccw
  arc A226 (43.7207, 20.9331) -> (43.9023, 21.1386) centre (43.6953, 21.1386) ccw
  arc A227 (43.9023, 21.1386) -> (43.7207, 21.344) centre (43.6953, 21.1386) ccw
  arc A228 (38.0458, 7.2069) -> (38.0458, 6.796) centre (38.0713, 7.0015) ccw
  arc A229 (38.0458, 8.2944) -> (38.0458, 7.8835) centre (38.0713, 8.0889) ccw
  arc A230 (38.0458, 3.9445) -> (38.0458, 3.5336) centre (38.0713, 3.739) ccw
  arc A231 (40.5167, 2.9899) -> (40.5167, 3.4007) centre (40.4913, 3.1953) ccw
  arc A232 (38.0458, 5.0319) -> (38.0458, 4.6211) centre (38.0713, 4.8265) ccw
  arc A233 (50.1287, 3.5336) -> (50.1287, 3.9445) centre (50.1033, 3.739) ccw
  arc A234 (47.6578, 3.4007) -> (47.6578, 2.9899) centre (47.6833, 3.1953) ccw
  arc A235 (50.1287, 4.6211) -> (50.1287, 5.0319) centre (50.1033, 4.8265) ccw
  arc A236 (41.2498, 3.4007) -> (41.2498, 2.9899) centre (41.2753, 3.1953) ccw
  arc A237 (46.9247, 2.9899) -> (46.9247, 3.4007) centre (46.8993, 3.1953) ccw
  arc A238 (43.7207, 4.6211) -> (43.7207, 5.0319) centre (43.6953, 4.8265) ccw
  arc A239 (44.4538, 5.0319) -> (44.4538, 4.6211) centre (44.4793, 4.8265) ccw
  arc A240 (38.0458, 2.857) -> (38.0458, 2.4461) centre (38.0713, 2.6516) ccw
  arc A241 (50.1287, 2.4461) -> (50.1287, 2.857) centre (50.1033, 2.6516) ccw
  arc A242 (41.2498, 7.7506) -> (41.2498, 7.3398) centre (41.2753, 7.5452) ccw
  arc A243 (40.5167, 7.3398) -> (40.5167, 7.7506) centre (40.4913, 7.5452) ccw
  arc A244 (47.6578, 7.7506) -> (47.6578, 7.3398) centre (47.6833, 7.5452) ccw
  arc A245 (46.9247, 7.3398) -> (46.9247, 7.7506) centre (46.8993, 7.5452) ccw
  arc A246 (40.5167, -4.6224) -> (40.5167, -4.2115) centre (40.4913, -4.417) ccw
  arc A247 (38.0458, -3.6678) -> (38.0458, -4.0787) centre (38.0713, -3.8732) ccw
  arc A248 (38.0458, -2.5803) -> (38.0458, -2.9912) centre (38.0713, -2.7858) ccw
  arc A249 (40.5167, -3.5349) -> (40.5167, -3.1241) centre (40.4913, -3.3295) ccw
  arc A250 (38.0458, -1.4929) -> (38.0458, -1.9037) centre (38.0713, -1.6983) ccw
  arc A251 (47.6578, -4.2115) -> (47.6578, -4.6224) centre (47.6833, -4.417) ccw
  arc A252 (50.1287, -4.0787) -> (50.1287, -3.6678) centre (50.1033, -3.8732) ccw
  arc A253 (50.1287, -2.9912) -> (50.1287, -2.5803) centre (50.1033, -2.7858) ccw
  arc A254 (47.6578, -3.1241) -> (47.6578, -3.5349) centre (47.6833, -3.3295) ccw
  arc A255 (50.1287, -1.9037) -> (50.1287, -1.4929) centre (50.1033, -1.6983) ccw
  arc A256 (41.2498, -4.2115) -> (41.2498, -4.6224) centre (41.2753, -4.417) ccw
  arc A257 (44.4538, -3.6678) -> (44.4538, -4.0787) centre (44.4793, -3.8732) ccw
  arc A258 (43.7207, -4.0787) -> (43.7207, -3.6678) centre (43.6953, -3.8732) ccw
  arc A259 (46.9247, -4.6224) -> (46.9247, -4.2115) centre (46.8993, -4.417) ccw
  arc A260 (44.4538, -2.5803) -> (44.4538, -2.9912) centre (44.4793, -2.7858) ccw
  arc A261 (43.7207, -2.9912) -> (43.7207, -2.5803) centre (43.6953, -2.7858) ccw
  arc A262 (41.2498, -3.1241) -> (41.2498, -3.5349) centre (41.2753, -3.3295) ccw
  arc A263 (46.9247, -3.5349) -> (46.9247, -3.1241) centre (46.8993, -3.3295) ccw
  arc A264 (40.4767, -2.4475) -> (40.6515, -2.3931) centre (40.418, -1.9508) ccw
  arc A265 (41.1151, -2.3931) -> (41.2898, -2.4475) centre (41.3485, -1.9508) ccw
  arc A266 (41.1151, -2.3931) -> (40.6515, -2.3931) centre (40.8833, -2.8498) ccw
  arc A267 (40.6515, -2.091) -> (41.1151, -2.091) centre (40.8833, -1.6361) ccw
  arc A268 (40.6515, -2.091) -> (40.4767, -2.0366) centre (40.418, -2.5333) ccw
  arc A269 (41.2898, -2.0366) -> (41.1151, -2.091) centre (41.3485, -2.5333) ccw
  arc A270 (40.5167, 0.8149) -> (40.5167, 1.2258) centre (40.4913, 1.0204) ccw
  arc A271 (41.2498, 1.2258) -> (41.2498, 0.8149) centre (41.2753, 1.0204) ccw
  arc A272 (40.4767, 1.9024) -> (40.6515, 1.9568) centre (40.418, 2.3991) ccw
  arc A273 (41.1151, 1.9568) -> (41.2898, 1.9024) centre (41.3485, 2.3991) ccw
  arc A274 (41.1151, 1.9568) -> (40.6515, 1.9568) centre (40.8833, 1.5001) ccw
  arc A275 (40.6515, 2.2589) -> (41.1151, 2.2589) centre (40.8833, 2.7138) ccw
  arc A276 (40.6515, 2.2589) -> (40.4767, 2.3133) centre (40.418, 1.8166) ccw
  arc A277 (41.2898, 2.3133) -> (41.1151, 2.2589) centre (41.3485, 1.8166) ccw
  arc A278 (40.5167, 5.1648) -> (40.5167, 5.5757) centre (40.4913, 5.3702) ccw
  arc A279 (41.2498, 5.5757) -> (41.2498, 5.1648) centre (41.2753, 5.3702) ccw
  arc A280 (40.5167, 9.5147) -> (40.5167, 9.9256) centre (40.4913, 9.7201) ccw
  arc A281 (41.2498, 9.9256) -> (41.2498, 9.5147) centre (41.2753, 9.7201) ccw
  arc A282 (40.4767, 10.6022) -> (40.6515, 10.6566) centre (40.418, 11.0988) ccw
  arc A283 (41.1151, 10.6566) -> (40.6515, 10.6566) centre (40.8833, 10.1998) ccw
  arc A284 (41.1151, 10.6566) -> (41.2898, 10.6022) centre (41.3485, 11.0988) ccw
  arc A285 (40.6515, 10.9586) -> (41.1151, 10.9586) centre (40.8833, 11.4135) ccw
  arc A286 (41.2898, 11.013) -> (41.1151, 10.9586) centre (41.3485, 10.5164) ccw
  arc A287 (40.6515, 10.9586) -> (40.4767, 11.013) centre (40.418, 10.5164) ccw
  arc A288 (40.5167, 13.8646) -> (40.5167, 14.2754) centre (40.4913, 14.07) ccw
  arc A289 (41.2498, 14.2754) -> (41.2498, 13.8646) centre (41.2753, 14.07) ccw
  arc A290 (41.2898, 15.3629) -> (41.1151, 15.3085) centre (41.3485, 14.8663) ccw
  arc A291 (40.6515, 15.3085) -> (40.4767, 15.3629) centre (40.418, 14.8663) ccw
  arc A292 (41.1151, 15.0064) -> (41.2898, 14.952) centre (41.3485, 15.4487) ccw
  arc A293 (40.4767, 14.952) -> (40.6515, 15.0064) centre (40.418, 15.4487) ccw
  arc A294 (40.6515, 15.3085) -> (41.1151, 15.3085) centre (40.8833, 15.7634) ccw
  arc A295 (41.1151, 15.0064) -> (40.6515, 15.0064) centre (40.8833, 14.5497) ccw
  arc A296 (40.5167, 18.2145) -> (40.5167, 18.6253) centre (40.4913, 18.4199) ccw
  arc A297 (41.2498, 18.6253) -> (41.2498, 18.2145) centre (41.2753, 18.4199) ccw
  arc A298 (40.6515, 19.6584) -> (40.4767, 19.7128) centre (40.418, 19.2161) ccw
  arc A299 (41.2898, 19.7128) -> (41.1151, 19.6584) centre (41.3485, 19.2161) ccw
  arc A300 (41.1151, 19.3563) -> (40.6515, 19.3563) centre (40.8833, 18.9014) ccw
  arc A301 (40.4767, 19.3019) -> (40.6515, 19.3563) centre (40.418, 19.7986) ccw
  arc A302 (41.1151, 19.3563) -> (41.2898, 19.3019) centre (41.3485, 19.7986) ccw
  arc A303 (40.6515, 19.6584) -> (41.1151, 19.6584) centre (40.8833, 20.1133) ccw
  arc A304 (44.4938, -1.4929) -> (44.3191, -1.5473) centre (44.5525, -1.9895) ccw
  arc A305 (43.8555, -1.5473) -> (43.6807, -1.4929) centre (43.622, -1.9895) ccw
  arc A306 (43.8555, -1.5473) -> (44.3191, -1.5473) centre (44.0873, -1.0924) ccw
  arc A307 (44.3191, -1.8494) -> (43.8555, -1.8494) centre (44.0873, -2.3061) ccw
  arc A308 (44.3191, -1.8494) -> (44.4938, -1.9037) centre (44.5525, -1.4071) ccw
  arc A309 (43.6807, -1.9037) -> (43.8555, -1.8494) centre (43.622, -1.4071) ccw
  arc A310 (44.4538, 1.7695) -> (44.4538, 1.3587) centre (44.4793, 1.5641) ccw
  arc A311 (43.7207, 1.3587) -> (43.7207, 1.7695) centre (43.6953, 1.5641) ccw
  arc A312 (44.3191, 2.5005) -> (43.8555, 2.5005) centre (44.0873, 2.0438) ccw
  arc A313 (44.3191, 2.5005) -> (44.4938, 2.4461) centre (44.5525, 2.9428) ccw
  arc A314 (43.6807, 2.4461) -> (43.8555, 2.5005) centre (43.622, 2.9428) ccw
  arc A315 (44.4938, 2.857) -> (44.3191, 2.8026) centre (44.5525, 2.3604) ccw
  arc A316 (43.8555, 2.8026) -> (43.6807, 2.857) centre (43.622, 2.3604) ccw
  arc A317 (43.8555, 2.8026) -> (44.3191, 2.8026) centre (44.0873, 3.2575) ccw
  arc A318 (44.4538, 6.1194) -> (44.4538, 5.7086) centre (44.4793, 5.914) ccw
  arc A319 (43.7207, 5.7086) -> (43.7207, 6.1194) centre (43.6953, 5.914) ccw
  arc A320 (43.8555, 7.1525) -> (44.3191, 7.1525) centre (44.0873, 7.6074) ccw
  arc A321 (43.8555, 7.1525) -> (43.6807, 7.2069) centre (43.622, 6.7102) ccw
  arc A322 (44.4938, 7.2069) -> (44.3191, 7.1525) centre (44.5525, 6.7102) ccw
  arc A323 (43.6807, 6.796) -> (43.8555, 6.8504) centre (43.622, 7.2927) ccw
  arc A324 (44.3191, 6.8504) -> (44.4938, 6.796) centre (44.5525, 7.2927) ccw
  arc A325 (44.3191, 6.8504) -> (43.8555, 6.8504) centre (44.0873, 6.3937) ccw
  arc A326 (43.8555, 11.5024) -> (43.6807, 11.5568) centre (43.622, 11.0601) ccw
  arc A327 (44.4938, 11.5568) -> (44.3191, 11.5024) centre (44.5525, 11.0601) ccw
  arc A328 (43.8555, 11.5024) -> (44.3191, 11.5024) centre (44.0873, 11.9573) ccw
  arc A329 (44.3191, 11.2003) -> (44.4938, 11.1459) centre (44.5525, 11.6426) ccw
  arc A330 (44.3191, 11.2003) -> (43.8555, 11.2003) centre (44.0873, 10.7436) ccw
  arc A331 (43.6807, 11.1459) -> (43.8555, 11.2003) centre (43.622, 11.6426) ccw
  arc A332 (43.8555, 15.8523) -> (44.3191, 15.8523) centre (44.0873, 16.3071) ccw
  arc A333 (43.8555, 15.8523) -> (43.6807, 15.9066) centre (43.622, 15.41) ccw
  arc A334 (44.4938, 15.9066) -> (44.3191, 15.8523) centre (44.5525, 15.41) ccw
  arc A335 (44.3191, 15.5502) -> (43.8555, 15.5502) centre (44.0873, 15.0934) ccw
  arc A336 (43.6807, 15.4958) -> (43.8555, 15.5502) centre (43.622, 15.9924) ccw
  arc A337 (44.3191, 15.5502) -> (44.4938, 15.4958) centre (44.5525, 15.9924) ccw
  arc A338 (43.8555, 20.2021) -> (44.3191, 20.2021) centre (44.0873, 20.657) ccw
  arc A339 (44.4938, 20.2565) -> (44.3191, 20.2021) centre (44.5525, 19.7599) ccw
  arc A340 (43.8555, 20.2021) -> (43.6807, 20.2565) centre (43.622, 19.7599) ccw
  arc A341 (44.3191, 19.9) -> (44.4938, 19.8457) centre (44.5525, 20.3423) ccw
  arc A342 (43.6807, 19.8457) -> (43.8555, 19.9) centre (43.622, 20.3423) ccw
  arc A343 (44.3191, 19.9) -> (43.8555, 19.9) centre (44.0873, 19.4452) ccw
  arc A344 (47.6774, 18.6253) -> (47.6774, 18.2145) centre (47.7028, 18.4199) ccw
  arc A345 (46.9443, 18.2145) -> (46.9443, 18.6253) centre (46.9188, 18.4199) ccw
  arc A346 (46.9247, 13.8646) -> (46.9247, 14.2754) centre (46.8993, 14.07) ccw
  arc A347 (47.6578, 14.2754) -> (47.6578, 13.8646) centre (47.6833, 14.07) ccw
  arc A348 (47.6578, 9.9256) -> (47.6578, 9.5147) centre (47.6833, 9.7201) ccw
  arc A349 (46.9247, 9.5147) -> (46.9247, 9.9256) centre (46.8993, 9.7201) ccw
  arc A350 (47.6578, 5.5757) -> (47.6578, 5.1648) centre (47.6833, 5.3702) ccw
  arc A351 (46.9247, 5.1648) -> (46.9247, 5.5757) centre (46.8993, 5.3702) ccw
  arc A352 (47.6578, 1.2258) -> (47.6578, 0.8149) centre (47.6833, 1.0204) ccw
  arc A353 (46.9247, 0.8149) -> (46.9247, 1.2258) centre (46.8993, 1.0204) ccw
  arc A354 (47.0595, -2.091) -> (46.8847, -2.0366) centre (46.826, -2.5333) ccw
  arc A355 (47.6978, -2.0366) -> (47.5231, -2.091) centre (47.7565, -2.5333) ccw
  arc A356 (47.0595, -2.091) -> (47.5231, -2.091) centre (47.2913, -1.6361) ccw
  arc A357 (46.8847, -2.4475) -> (47.0595, -2.3931) centre (46.826, -1.9508) ccw
  arc A358 (47.5231, -2.3931) -> (47.6978, -2.4475) centre (47.7565, -1.9508) ccw
  arc A359 (47.5231, -2.3931) -> (47.0595, -2.3931) centre (47.2913, -2.8498) ccw
extrude "Linear austragen1" add sketch "Skizze1" along normal blind 0.2
